VERSION 5.8 ;
BUSBITCHARS "[]" ;
DIVIDERCHAR "/" ;
UNITS
    DATABASE MICRONS 1000 ;
END UNITS

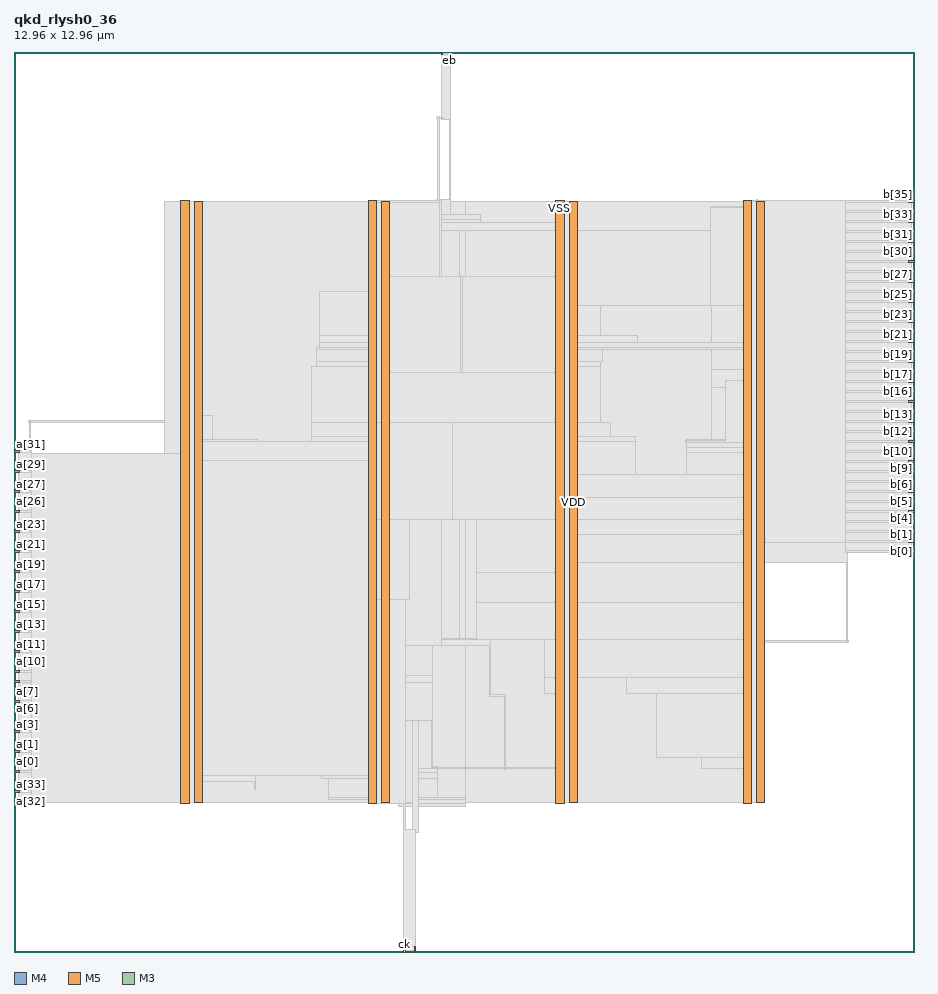
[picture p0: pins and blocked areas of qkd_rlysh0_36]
MACRO qkd_rlysh0_36
  FOREIGN qkd_rlysh0_36 0 0 ;
  CLASS BLOCK ;
  SIZE 12.96 BY 12.96 ;
  PIN a[0]
    DIRECTION INPUT ;
    USE SIGNAL ;
    PORT
      LAYER M4 ;
        RECT  0 2.736 0.084 2.76 ;
    END
  END a[0]
  PIN a[10]
    DIRECTION INPUT ;
    USE SIGNAL ;
    PORT
      LAYER M4 ;
        RECT  0 4.176 0.084 4.2 ;
    END
  END a[10]
  PIN a[11]
    DIRECTION INPUT ;
    USE SIGNAL ;
    PORT
      LAYER M4 ;
        RECT  0 4.32 0.084 4.344 ;
    END
  END a[11]
  PIN a[12]
    DIRECTION INPUT ;
    USE SIGNAL ;
    PORT
      LAYER M4 ;
        RECT  0 4.464 0.084 4.488 ;
    END
  END a[12]
  PIN a[13]
    DIRECTION INPUT ;
    USE SIGNAL ;
    PORT
      LAYER M4 ;
        RECT  0 4.608 0.084 4.632 ;
    END
  END a[13]
  PIN a[14]
    DIRECTION INPUT ;
    USE SIGNAL ;
    PORT
      LAYER M4 ;
        RECT  0 4.752 0.084 4.776 ;
    END
  END a[14]
  PIN a[15]
    DIRECTION INPUT ;
    USE SIGNAL ;
    PORT
      LAYER M4 ;
        RECT  0 4.896 0.084 4.92 ;
    END
  END a[15]
  PIN a[16]
    DIRECTION INPUT ;
    USE SIGNAL ;
    PORT
      LAYER M4 ;
        RECT  0 5.04 0.084 5.064 ;
    END
  END a[16]
  PIN a[17]
    DIRECTION INPUT ;
    USE SIGNAL ;
    PORT
      LAYER M4 ;
        RECT  0 5.184 0.084 5.208 ;
    END
  END a[17]
  PIN a[18]
    DIRECTION INPUT ;
    USE SIGNAL ;
    PORT
      LAYER M4 ;
        RECT  0 5.328 0.084 5.352 ;
    END
  END a[18]
  PIN a[19]
    DIRECTION INPUT ;
    USE SIGNAL ;
    PORT
      LAYER M4 ;
        RECT  0 5.472 0.084 5.496 ;
    END
  END a[19]
  PIN a[1]
    DIRECTION INPUT ;
    USE SIGNAL ;
    PORT
      LAYER M4 ;
        RECT  0 2.88 0.084 2.904 ;
    END
  END a[1]
  PIN a[20]
    DIRECTION INPUT ;
    USE SIGNAL ;
    PORT
      LAYER M4 ;
        RECT  0 5.616 0.084 5.64 ;
    END
  END a[20]
  PIN a[21]
    DIRECTION INPUT ;
    USE SIGNAL ;
    PORT
      LAYER M4 ;
        RECT  0 5.76 0.084 5.784 ;
    END
  END a[21]
  PIN a[22]
    DIRECTION INPUT ;
    USE SIGNAL ;
    PORT
      LAYER M4 ;
        RECT  0 5.904 0.084 5.928 ;
    END
  END a[22]
  PIN a[23]
    DIRECTION INPUT ;
    USE SIGNAL ;
    PORT
      LAYER M4 ;
        RECT  0 6.048 0.084 6.072 ;
    END
  END a[23]
  PIN a[24]
    DIRECTION INPUT ;
    USE SIGNAL ;
    PORT
      LAYER M4 ;
        RECT  0 6.192 0.084 6.216 ;
    END
  END a[24]
  PIN a[25]
    DIRECTION INPUT ;
    USE SIGNAL ;
    PORT
      LAYER M4 ;
        RECT  0 6.336 0.084 6.36 ;
    END
  END a[25]
  PIN a[26]
    DIRECTION INPUT ;
    USE SIGNAL ;
    PORT
      LAYER M4 ;
        RECT  0 6.48 0.084 6.504 ;
    END
  END a[26]
  PIN a[27]
    DIRECTION INPUT ;
    USE SIGNAL ;
    PORT
      LAYER M4 ;
        RECT  0 6.624 0.084 6.648 ;
    END
  END a[27]
  PIN a[28]
    DIRECTION INPUT ;
    USE SIGNAL ;
    PORT
      LAYER M4 ;
        RECT  0 6.768 0.084 6.792 ;
    END
  END a[28]
  PIN a[29]
    DIRECTION INPUT ;
    USE SIGNAL ;
    PORT
      LAYER M4 ;
        RECT  0 6.912 0.084 6.936 ;
    END
  END a[29]
  PIN a[2]
    DIRECTION INPUT ;
    USE SIGNAL ;
    PORT
      LAYER M4 ;
        RECT  0 3.024 0.084 3.048 ;
    END
  END a[2]
  PIN a[30]
    DIRECTION INPUT ;
    USE SIGNAL ;
    PORT
      LAYER M4 ;
        RECT  0 7.056 0.084 7.08 ;
    END
  END a[30]
  PIN a[31]
    DIRECTION INPUT ;
    USE SIGNAL ;
    PORT
      LAYER M4 ;
        RECT  0 7.2 0.084 7.224 ;
    END
  END a[31]
  PIN a[32]
    DIRECTION INPUT ;
    USE SIGNAL ;
    PORT
      LAYER M4 ;
        RECT  0 2.16 0.084 2.184 ;
    END
  END a[32]
  PIN a[33]
    DIRECTION INPUT ;
    USE SIGNAL ;
    PORT
      LAYER M4 ;
        RECT  0 2.304 0.084 2.328 ;
    END
  END a[33]
  PIN a[34]
    DIRECTION INPUT ;
    USE SIGNAL ;
    PORT
      LAYER M4 ;
        RECT  0 2.448 0.084 2.472 ;
    END
  END a[34]
  PIN a[35]
    DIRECTION INPUT ;
    USE SIGNAL ;
    PORT
      LAYER M4 ;
        RECT  0 2.592 0.084 2.616 ;
    END
  END a[35]
  PIN a[3]
    DIRECTION INPUT ;
    USE SIGNAL ;
    PORT
      LAYER M4 ;
        RECT  0 3.168 0.084 3.192 ;
    END
  END a[3]
  PIN a[4]
    DIRECTION INPUT ;
    USE SIGNAL ;
    PORT
      LAYER M4 ;
        RECT  0 3.312 0.084 3.336 ;
    END
  END a[4]
  PIN a[5]
    DIRECTION INPUT ;
    USE SIGNAL ;
    PORT
      LAYER M4 ;
        RECT  0 3.456 0.084 3.48 ;
    END
  END a[5]
  PIN a[6]
    DIRECTION INPUT ;
    USE SIGNAL ;
    PORT
      LAYER M4 ;
        RECT  0 3.6 0.084 3.624 ;
    END
  END a[6]
  PIN a[7]
    DIRECTION INPUT ;
    USE SIGNAL ;
    PORT
      LAYER M4 ;
        RECT  0 3.744 0.084 3.768 ;
    END
  END a[7]
  PIN a[8]
    DIRECTION INPUT ;
    USE SIGNAL ;
    PORT
      LAYER M4 ;
        RECT  0 3.888 0.084 3.912 ;
    END
  END a[8]
  PIN a[9]
    DIRECTION INPUT ;
    USE SIGNAL ;
    PORT
      LAYER M4 ;
        RECT  0 4.032 0.084 4.056 ;
    END
  END a[9]
  PIN b[0]
    DIRECTION OUTPUT ;
    USE SIGNAL ;
    PORT
      LAYER M4 ;
        RECT  12.876 5.76 12.96 5.784 ;
    END
  END b[0]
  PIN b[10]
    DIRECTION OUTPUT ;
    USE SIGNAL ;
    PORT
      LAYER M4 ;
        RECT  12.876 7.2 12.96 7.224 ;
    END
  END b[10]
  PIN b[11]
    DIRECTION OUTPUT ;
    USE SIGNAL ;
    PORT
      LAYER M4 ;
        RECT  12.876 7.344 12.96 7.368 ;
    END
  END b[11]
  PIN b[12]
    DIRECTION OUTPUT ;
    USE SIGNAL ;
    PORT
      LAYER M4 ;
        RECT  12.876 7.488 12.96 7.512 ;
    END
  END b[12]
  PIN b[13]
    DIRECTION OUTPUT ;
    USE SIGNAL ;
    PORT
      LAYER M4 ;
        RECT  12.876 7.632 12.96 7.656 ;
    END
  END b[13]
  PIN b[14]
    DIRECTION OUTPUT ;
    USE SIGNAL ;
    PORT
      LAYER M4 ;
        RECT  12.876 7.776 12.96 7.8 ;
    END
  END b[14]
  PIN b[15]
    DIRECTION OUTPUT ;
    USE SIGNAL ;
    PORT
      LAYER M4 ;
        RECT  12.876 7.92 12.96 7.944 ;
    END
  END b[15]
  PIN b[16]
    DIRECTION OUTPUT ;
    USE SIGNAL ;
    PORT
      LAYER M4 ;
        RECT  12.876 8.064 12.96 8.088 ;
    END
  END b[16]
  PIN b[17]
    DIRECTION OUTPUT ;
    USE SIGNAL ;
    PORT
      LAYER M4 ;
        RECT  12.876 8.208 12.96 8.232 ;
    END
  END b[17]
  PIN b[18]
    DIRECTION OUTPUT ;
    USE SIGNAL ;
    PORT
      LAYER M4 ;
        RECT  12.876 8.352 12.96 8.376 ;
    END
  END b[18]
  PIN b[19]
    DIRECTION OUTPUT ;
    USE SIGNAL ;
    PORT
      LAYER M4 ;
        RECT  12.876 8.496 12.96 8.52 ;
    END
  END b[19]
  PIN b[1]
    DIRECTION OUTPUT ;
    USE SIGNAL ;
    PORT
      LAYER M4 ;
        RECT  12.876 5.904 12.96 5.928 ;
    END
  END b[1]
  PIN b[20]
    DIRECTION OUTPUT ;
    USE SIGNAL ;
    PORT
      LAYER M4 ;
        RECT  12.876 8.64 12.96 8.664 ;
    END
  END b[20]
  PIN b[21]
    DIRECTION OUTPUT ;
    USE SIGNAL ;
    PORT
      LAYER M4 ;
        RECT  12.876 8.784 12.96 8.808 ;
    END
  END b[21]
  PIN b[22]
    DIRECTION OUTPUT ;
    USE SIGNAL ;
    PORT
      LAYER M4 ;
        RECT  12.876 8.928 12.96 8.952 ;
    END
  END b[22]
  PIN b[23]
    DIRECTION OUTPUT ;
    USE SIGNAL ;
    PORT
      LAYER M4 ;
        RECT  12.876 9.072 12.96 9.096 ;
    END
  END b[23]
  PIN b[24]
    DIRECTION OUTPUT ;
    USE SIGNAL ;
    PORT
      LAYER M4 ;
        RECT  12.876 9.216 12.96 9.24 ;
    END
  END b[24]
  PIN b[25]
    DIRECTION OUTPUT ;
    USE SIGNAL ;
    PORT
      LAYER M4 ;
        RECT  12.876 9.36 12.96 9.384 ;
    END
  END b[25]
  PIN b[26]
    DIRECTION OUTPUT ;
    USE SIGNAL ;
    PORT
      LAYER M4 ;
        RECT  12.876 9.504 12.96 9.528 ;
    END
  END b[26]
  PIN b[27]
    DIRECTION OUTPUT ;
    USE SIGNAL ;
    PORT
      LAYER M4 ;
        RECT  12.876 9.648 12.96 9.672 ;
    END
  END b[27]
  PIN b[28]
    DIRECTION OUTPUT ;
    USE SIGNAL ;
    PORT
      LAYER M4 ;
        RECT  12.876 9.792 12.96 9.816 ;
    END
  END b[28]
  PIN b[29]
    DIRECTION OUTPUT ;
    USE SIGNAL ;
    PORT
      LAYER M4 ;
        RECT  12.876 9.936 12.96 9.96 ;
    END
  END b[29]
  PIN b[2]
    DIRECTION OUTPUT ;
    USE SIGNAL ;
    PORT
      LAYER M4 ;
        RECT  12.876 6.048 12.96 6.072 ;
    END
  END b[2]
  PIN b[30]
    DIRECTION OUTPUT ;
    USE SIGNAL ;
    PORT
      LAYER M4 ;
        RECT  12.876 10.08 12.96 10.104 ;
    END
  END b[30]
  PIN b[31]
    DIRECTION OUTPUT ;
    USE SIGNAL ;
    PORT
      LAYER M4 ;
        RECT  12.876 10.224 12.96 10.248 ;
    END
  END b[31]
  PIN b[32]
    DIRECTION OUTPUT ;
    USE SIGNAL ;
    PORT
      LAYER M4 ;
        RECT  12.876 10.368 12.96 10.392 ;
    END
  END b[32]
  PIN b[33]
    DIRECTION OUTPUT ;
    USE SIGNAL ;
    PORT
      LAYER M4 ;
        RECT  12.876 10.512 12.96 10.536 ;
    END
  END b[33]
  PIN b[34]
    DIRECTION OUTPUT ;
    USE SIGNAL ;
    PORT
      LAYER M4 ;
        RECT  12.876 10.656 12.96 10.68 ;
    END
  END b[34]
  PIN b[35]
    DIRECTION OUTPUT ;
    USE SIGNAL ;
    PORT
      LAYER M4 ;
        RECT  12.876 10.8 12.96 10.824 ;
    END
  END b[35]
  PIN b[3]
    DIRECTION OUTPUT ;
    USE SIGNAL ;
    PORT
      LAYER M4 ;
        RECT  12.876 6.192 12.96 6.216 ;
    END
  END b[3]
  PIN b[4]
    DIRECTION OUTPUT ;
    USE SIGNAL ;
    PORT
      LAYER M4 ;
        RECT  12.876 6.336 12.96 6.36 ;
    END
  END b[4]
  PIN b[5]
    DIRECTION OUTPUT ;
    USE SIGNAL ;
    PORT
      LAYER M4 ;
        RECT  12.876 6.48 12.96 6.504 ;
    END
  END b[5]
  PIN b[6]
    DIRECTION OUTPUT ;
    USE SIGNAL ;
    PORT
      LAYER M4 ;
        RECT  12.876 6.624 12.96 6.648 ;
    END
  END b[6]
  PIN b[7]
    DIRECTION OUTPUT ;
    USE SIGNAL ;
    PORT
      LAYER M4 ;
        RECT  12.876 6.768 12.96 6.792 ;
    END
  END b[7]
  PIN b[8]
    DIRECTION OUTPUT ;
    USE SIGNAL ;
    PORT
      LAYER M4 ;
        RECT  12.876 6.912 12.96 6.936 ;
    END
  END b[8]
  PIN b[9]
    DIRECTION OUTPUT ;
    USE SIGNAL ;
    PORT
      LAYER M4 ;
        RECT  12.876 7.056 12.96 7.08 ;
    END
  END b[9]
  PIN ck
    DIRECTION INPUT ;
    USE SIGNAL ;
    PORT
      LAYER M5 ;
        RECT  5.616 0 5.64 0.084 ;
    END
  END ck
  PIN ck_o
    DIRECTION OUTPUT ;
    USE SIGNAL ;
    PORT
      LAYER M3 ;
        RECT  6.156 12.923 6.174 12.96 ;
    END
  END ck_o
  PIN eb
    DIRECTION OUTPUT ;
    USE SIGNAL ;
    PORT
      LAYER M3 ;
        RECT  6.264 12.923 6.282 12.96 ;
    END
  END eb
  PIN en
    DIRECTION INPUT ;
    USE SIGNAL ;
    PORT
      LAYER M5 ;
        RECT  5.76 0 5.784 0.084 ;
    END
  END en
  PIN VDD
    DIRECTION INOUT ;
    USE POWER ;
    PORT
      LAYER M5 ;
        RECT  10.692 2.151 10.812 10.809 ;
        RECT  7.992 2.151 8.112 10.809 ;
        RECT  5.292 2.151 5.412 10.809 ;
        RECT  2.592 2.151 2.712 10.809 ;
    END
  END VDD
  PIN VSS
    DIRECTION INOUT ;
    USE GROUND ;
    PORT
      LAYER M5 ;
        RECT  10.5 2.137 10.62 10.823 ;
        RECT  7.8 2.137 7.92 10.823 ;
        RECT  5.1 2.137 5.22 10.823 ;
        RECT  2.4 2.137 2.52 10.823 ;
    END
  END VSS
  # OT_OBS_CLOSED layer=M5 d_um=1.536 added=5
  OBS
    LAYER RVTN ;
     RECT  2.16 2.16 10.8 2.295 ;
     RECT  2.16 2.565 10.8 2.835 ;
     RECT  2.16 3.105 10.8 3.375 ;
     RECT  2.16 3.645 10.8 3.915 ;
     RECT  2.16 4.185 10.8 4.455 ;
     RECT  2.16 4.725 10.8 4.995 ;
     RECT  2.16 5.265 10.8 5.535 ;
     RECT  2.16 5.805 10.8 6.075 ;
     RECT  2.16 6.345 10.8 6.615 ;
     RECT  2.16 6.885 10.8 7.155 ;
     RECT  2.16 7.425 10.8 7.695 ;
     RECT  2.16 7.965 10.8 8.235 ;
     RECT  2.16 8.505 10.8 8.775 ;
     RECT  2.16 9.045 10.8 9.315 ;
     RECT  2.16 9.585 10.8 9.855 ;
     RECT  2.16 10.125 10.8 10.395 ;
     RECT  2.16 10.665 10.8 10.8 ;
    LAYER RVTP ;
     RECT  2.16 2.295 10.8 2.565 ;
     RECT  2.16 2.835 10.8 3.105 ;
     RECT  2.16 3.375 10.8 3.645 ;
     RECT  2.16 3.915 10.8 4.185 ;
     RECT  2.16 4.455 10.8 4.725 ;
     RECT  2.16 4.995 10.8 5.265 ;
     RECT  2.16 5.535 10.8 5.805 ;
     RECT  2.16 6.075 10.8 6.345 ;
     RECT  2.16 6.615 10.8 6.885 ;
     RECT  2.16 7.155 10.8 7.425 ;
     RECT  2.16 7.695 10.8 7.965 ;
     RECT  2.16 8.235 10.8 8.505 ;
     RECT  2.16 8.775 10.8 9.045 ;
     RECT  2.16 9.315 10.8 9.585 ;
     RECT  2.16 9.855 10.8 10.125 ;
     RECT  2.16 10.395 10.8 10.665 ;
    LAYER M1 ;
     RECT  2.16 2.151 10.8 10.809 ;
    LAYER M2 ;
     RECT  0.103 6.048 0.239 6.066 ;
     RECT  0.211 7.632 2.16 7.65 ;
     RECT  2.16 2.151 5.539 10.809 ;
     RECT  5.539 2.106 6.503 10.809 ;
     RECT  6.503 2.151 10.8 10.809 ;
     RECT  10.8 2.421 10.812 10.539 ;
     RECT  10.812 5.616 10.859 9.774 ;
     RECT  10.859 5.616 11.435 9.684 ;
     RECT  10.812 4.464 12.011 4.482 ;
     RECT  11.435 5.886 12.011 9.108 ;
     RECT  12.011 6.012 12.047 7.344 ;
     RECT  12.011 8.586 12.047 9.108 ;
     RECT  12.047 6.012 12.083 6.174 ;
     RECT  12.083 6.012 12.119 6.03 ;
     RECT  12.047 7.092 12.155 7.11 ;
     RECT  12.047 9.09 12.155 9.108 ;
    LAYER M3 ;
     RECT  5.796 1.723 5.814 2.101 ;
     RECT  5.544 2.101 6.498 2.143 ;
     RECT  2.415 2.143 2.505 2.155 ;
     RECT  5.115 2.143 6.498 2.191 ;
     RECT  4.536 2.191 6.498 2.219 ;
     RECT  2.304 2.155 2.505 2.413 ;
     RECT  7.815 2.143 7.905 2.413 ;
     RECT  10.515 2.143 10.605 2.413 ;
     RECT  2.304 2.413 2.697 2.443 ;
     RECT  2.268 2.443 2.697 2.461 ;
     RECT  3.456 2.335 3.474 2.461 ;
     RECT  4.536 2.219 6.102 2.497 ;
     RECT  2.268 2.461 3.474 2.573 ;
     RECT  2.304 2.573 3.474 2.587 ;
     RECT  4.428 2.497 6.102 2.587 ;
     RECT  10.515 2.413 10.797 2.641 ;
     RECT  2.304 2.587 6.102 2.669 ;
     RECT  9.9 2.641 10.797 2.803 ;
     RECT  2.304 2.669 6.03 3.065 ;
     RECT  2.304 3.065 3.402 3.643 ;
     RECT  7.056 2.635 7.074 3.685 ;
     RECT  6.84 3.685 7.074 3.713 ;
     RECT  7.815 2.413 8.097 3.721 ;
     RECT  9.252 2.803 10.797 3.721 ;
     RECT  2.268 3.643 3.402 3.773 ;
     RECT  2.304 3.773 3.402 3.883 ;
     RECT  4.14 3.065 6.03 3.883 ;
     RECT  7.632 3.721 8.097 3.955 ;
     RECT  8.82 3.721 10.797 3.955 ;
     RECT  2.304 3.883 6.03 3.983 ;
     RECT  3.456 3.983 6.03 4.411 ;
     RECT  6.84 3.713 6.858 4.411 ;
     RECT  3.456 4.411 6.858 4.495 ;
     RECT  7.632 3.955 10.797 4.495 ;
     RECT  0.144 4.315 0.162 4.891 ;
     RECT  0.144 4.891 0.198 5.021 ;
     RECT  2.304 3.983 2.697 5.035 ;
     RECT  3.456 4.495 10.797 5.035 ;
     RECT  2.304 5.035 10.797 5.611 ;
     RECT  11.988 4.459 12.006 5.611 ;
     RECT  0.144 5.021 0.162 5.899 ;
     RECT  2.304 5.611 12.006 6.007 ;
     RECT  0.144 5.899 0.342 6.043 ;
     RECT  0.108 6.043 0.342 6.077 ;
     RECT  0.108 6.077 0.126 6.08 ;
     RECT  2.304 6.007 12.114 6.221 ;
     RECT  2.304 6.221 11.142 6.539 ;
     RECT  2.415 6.539 11.142 6.881 ;
     RECT  11.988 6.221 12.114 7.087 ;
     RECT  0.144 7.051 0.162 7.181 ;
     RECT  9.684 6.881 11.142 7.195 ;
     RECT  11.988 7.087 12.15 7.195 ;
     RECT  9.684 7.195 12.15 7.259 ;
     RECT  2.415 6.881 8.946 7.349 ;
     RECT  9.684 7.259 10.854 7.373 ;
     RECT  2.415 7.349 3.51 7.385 ;
     RECT  9.72 7.373 10.854 7.385 ;
     RECT  4.284 7.349 8.946 7.421 ;
     RECT  4.284 7.421 8.586 7.619 ;
     RECT  0.216 7.195 0.234 7.655 ;
     RECT  2.415 7.385 2.862 7.727 ;
     RECT  10.044 7.385 10.854 8.131 ;
     RECT  10.044 8.131 10.89 8.381 ;
     RECT  4.284 7.619 8.442 8.429 ;
     RECT  4.356 8.429 8.442 8.509 ;
     RECT  4.356 8.509 8.478 8.671 ;
     RECT  10.044 8.381 10.797 8.671 ;
     RECT  4.356 8.671 10.797 8.699 ;
     RECT  4.392 8.699 10.797 8.771 ;
     RECT  4.392 8.771 8.982 8.879 ;
     RECT  11.988 7.259 12.15 9.211 ;
     RECT  11.988 9.211 12.798 9.341 ;
     RECT  4.392 8.879 8.442 9.509 ;
     RECT  10.044 8.771 10.797 9.589 ;
     RECT  10.044 9.589 10.89 9.661 ;
     RECT  11.988 9.341 12.078 9.661 ;
     RECT  10.044 9.661 12.078 9.677 ;
     RECT  5.115 9.509 8.442 9.779 ;
     RECT  10.044 9.677 11.43 10.109 ;
     RECT  5.115 9.779 8.097 10.499 ;
     RECT  10.044 10.109 10.89 10.541 ;
     RECT  2.415 7.727 2.697 10.547 ;
     RECT  5.115 10.499 6.714 10.547 ;
     RECT  7.815 10.499 8.097 10.547 ;
     RECT  10.044 10.541 10.797 10.547 ;
     RECT  5.976 10.547 6.714 10.625 ;
     RECT  10.044 10.547 10.71 10.733 ;
     RECT  2.415 10.547 2.505 10.817 ;
     RECT  5.115 10.547 5.205 10.817 ;
     RECT  7.815 10.547 7.905 10.817 ;
     RECT  10.515 10.733 10.71 10.817 ;
     RECT  6.084 10.625 6.282 10.829 ;
     RECT  10.692 10.817 10.71 10.829 ;
     RECT  6.264 10.829 6.282 11.995 ;
     RECT  6.156 11.995 6.282 12.923 ;
     RECT  6.174 12.923 6.264 12.941 ;
    LAYER M4 ;
     RECT  0.084 2.16 0.245 2.184 ;
     RECT  0.06 2.184 0.245 2.304 ;
     RECT  0.084 2.304 0.245 2.328 ;
     RECT  0.06 2.328 0.245 2.448 ;
     RECT  0.084 2.448 0.245 2.472 ;
     RECT  0.06 2.472 0.245 2.592 ;
     RECT  0.084 2.592 0.245 2.616 ;
     RECT  0.06 2.616 0.245 2.736 ;
     RECT  0.084 2.736 0.245 2.76 ;
     RECT  0.06 2.76 0.245 2.88 ;
     RECT  0.084 2.88 0.245 2.904 ;
     RECT  0.06 2.904 0.245 3.024 ;
     RECT  0.084 3.024 0.245 3.048 ;
     RECT  0.06 3.048 0.245 3.168 ;
     RECT  0.084 3.168 0.245 3.192 ;
     RECT  0.06 3.192 0.245 3.312 ;
     RECT  0.084 3.312 0.245 3.336 ;
     RECT  0.06 3.336 0.245 3.456 ;
     RECT  0.084 3.456 0.245 3.48 ;
     RECT  0.06 3.48 0.245 3.6 ;
     RECT  0.084 3.6 0.245 3.624 ;
     RECT  0.06 3.624 0.245 3.744 ;
     RECT  0.084 3.744 0.245 3.768 ;
     RECT  0.06 3.768 0.245 3.888 ;
     RECT  0.084 3.888 0.245 3.912 ;
     RECT  0.06 3.912 0.245 4.032 ;
     RECT  0.084 4.032 0.245 4.056 ;
     RECT  0.06 4.056 0.245 4.176 ;
     RECT  0.084 4.176 0.245 4.2 ;
     RECT  0.06 4.2 0.245 4.32 ;
     RECT  0.084 4.32 0.245 4.344 ;
     RECT  0.06 4.344 0.245 4.464 ;
     RECT  0.084 4.464 0.245 4.488 ;
     RECT  0.06 4.488 0.245 4.608 ;
     RECT  0.084 4.608 0.245 4.632 ;
     RECT  0.06 4.632 0.245 4.752 ;
     RECT  0.084 4.752 0.245 4.776 ;
     RECT  0.06 4.776 0.245 4.896 ;
     RECT  0.084 4.896 0.245 4.92 ;
     RECT  0.06 4.92 0.245 5.04 ;
     RECT  0.084 5.04 0.245 5.064 ;
     RECT  0.06 5.064 0.245 5.184 ;
     RECT  0.084 5.184 0.245 5.208 ;
     RECT  0.06 5.208 0.245 5.328 ;
     RECT  0.084 5.328 0.245 5.352 ;
     RECT  0.06 5.352 0.245 5.472 ;
     RECT  0.084 5.472 0.245 5.496 ;
     RECT  0.06 5.496 0.245 5.616 ;
     RECT  0.084 5.616 0.245 5.64 ;
     RECT  0.06 5.64 0.245 5.76 ;
     RECT  0.084 5.76 0.245 5.784 ;
     RECT  0.06 5.784 0.245 5.904 ;
     RECT  0.084 5.904 0.245 5.928 ;
     RECT  0.06 5.928 0.245 6.048 ;
     RECT  0.084 6.048 0.245 6.072 ;
     RECT  0.06 6.072 0.245 6.192 ;
     RECT  0.084 6.192 0.245 6.216 ;
     RECT  0.06 6.216 0.245 6.336 ;
     RECT  0.084 6.336 0.245 6.36 ;
     RECT  0.06 6.36 0.245 6.48 ;
     RECT  0.084 6.48 0.245 6.504 ;
     RECT  0.06 6.504 0.245 6.624 ;
     RECT  0.084 6.624 0.245 6.648 ;
     RECT  0.06 6.648 0.245 6.768 ;
     RECT  0.084 6.768 0.245 6.792 ;
     RECT  0.06 6.792 0.245 6.912 ;
     RECT  0.084 6.912 0.245 6.936 ;
     RECT  0.06 6.936 0.245 7.056 ;
     RECT  0.084 7.056 0.245 7.08 ;
     RECT  0.06 7.08 0.245 7.2 ;
     RECT  0.084 7.2 0.245 7.224 ;
     RECT  0.245 2.16 2.408 7.176 ;
     RECT  2.408 2.148 2.512 10.812 ;
     RECT  2.512 2.418 2.704 10.542 ;
     RECT  2.704 2.544 5.108 7.08 ;
     RECT  5.108 2.148 5.404 10.812 ;
     RECT  5.404 2.148 5.465 7.608 ;
     RECT  5.465 2.148 5.741 3.336 ;
     RECT  5.741 1.728 5.825 3.336 ;
     RECT  5.825 2.64 6.005 3.336 ;
     RECT  5.404 9.216 6.073 10.812 ;
     RECT  5.465 4.416 6.149 7.608 ;
     RECT  6.073 9.216 6.157 10.824 ;
     RECT  6.085 12 6.185 12.024 ;
     RECT  6.149 4.512 6.421 7.608 ;
     RECT  6.157 9.216 6.421 10.392 ;
     RECT  6.421 4.512 6.508 10.392 ;
     RECT  6.508 4.512 6.653 7.704 ;
     RECT  6.005 2.64 7.808 2.664 ;
     RECT  6.653 5.472 7.808 7.704 ;
     RECT  6.508 9.216 7.808 10.392 ;
     RECT  7.808 2.148 7.912 10.812 ;
     RECT  7.912 2.418 8.104 10.542 ;
     RECT  8.104 9.312 10.033 10.392 ;
     RECT  9.673 7.344 10.249 7.368 ;
     RECT  10.465 6.048 10.508 6.072 ;
     RECT  10.249 7.344 10.508 8.232 ;
     RECT  10.033 9.312 10.508 10.728 ;
     RECT  10.508 2.148 10.612 10.812 ;
     RECT  10.612 2.418 10.681 10.812 ;
     RECT  10.681 2.418 10.804 10.824 ;
     RECT  10.804 5.904 11.977 10.824 ;
     RECT  11.977 5.76 12.876 5.784 ;
     RECT  11.977 5.784 12.924 5.904 ;
     RECT  11.977 5.904 12.876 5.928 ;
     RECT  11.977 5.928 12.924 6.048 ;
     RECT  11.977 6.048 12.876 6.072 ;
     RECT  11.977 6.072 12.924 6.192 ;
     RECT  11.977 6.192 12.876 6.216 ;
     RECT  11.977 6.216 12.924 6.336 ;
     RECT  11.977 6.336 12.876 6.36 ;
     RECT  11.977 6.36 12.924 6.48 ;
     RECT  11.977 6.48 12.876 6.504 ;
     RECT  11.977 6.504 12.924 6.624 ;
     RECT  11.977 6.624 12.876 6.648 ;
     RECT  11.977 6.648 12.924 6.768 ;
     RECT  11.977 6.768 12.876 6.792 ;
     RECT  11.977 6.792 12.924 6.912 ;
     RECT  11.977 6.912 12.876 6.936 ;
     RECT  11.977 6.936 12.924 7.056 ;
     RECT  11.977 7.056 12.876 7.08 ;
     RECT  11.977 7.08 12.924 7.2 ;
     RECT  11.977 7.2 12.876 7.224 ;
     RECT  11.977 7.224 12.924 7.344 ;
     RECT  11.977 7.344 12.876 7.368 ;
     RECT  11.977 7.368 12.924 7.488 ;
     RECT  11.977 7.488 12.876 7.512 ;
     RECT  11.977 7.512 12.924 7.632 ;
     RECT  11.977 7.632 12.876 7.656 ;
     RECT  11.977 7.656 12.924 7.776 ;
     RECT  11.977 7.776 12.876 7.8 ;
     RECT  11.977 7.8 12.924 7.92 ;
     RECT  11.977 7.92 12.876 7.944 ;
     RECT  11.977 7.944 12.924 8.064 ;
     RECT  11.977 8.064 12.876 8.088 ;
     RECT  11.977 8.088 12.924 8.208 ;
     RECT  11.977 8.208 12.876 8.232 ;
     RECT  11.977 8.232 12.924 8.352 ;
     RECT  11.977 8.352 12.876 8.376 ;
     RECT  11.977 8.376 12.924 8.496 ;
     RECT  11.977 8.496 12.876 8.52 ;
     RECT  11.977 8.52 12.924 8.64 ;
     RECT  11.977 8.64 12.876 8.664 ;
     RECT  11.977 8.664 12.924 8.784 ;
     RECT  11.977 8.784 12.876 8.808 ;
     RECT  11.977 8.808 12.924 8.928 ;
     RECT  11.977 8.928 12.876 8.952 ;
     RECT  11.977 8.952 12.924 9.072 ;
     RECT  11.977 9.072 12.876 9.096 ;
     RECT  11.977 9.096 12.924 9.216 ;
     RECT  11.977 9.216 12.876 9.24 ;
     RECT  11.977 9.24 12.924 9.36 ;
     RECT  11.977 9.36 12.876 9.384 ;
     RECT  11.977 9.384 12.924 9.504 ;
     RECT  11.977 9.504 12.876 9.528 ;
     RECT  11.977 9.528 12.924 9.648 ;
     RECT  11.977 9.648 12.876 9.672 ;
     RECT  11.977 9.672 12.924 9.792 ;
     RECT  11.977 9.792 12.876 9.816 ;
     RECT  11.977 9.816 12.924 9.936 ;
     RECT  11.977 9.936 12.876 9.96 ;
     RECT  11.977 9.96 12.924 10.08 ;
     RECT  11.977 10.08 12.876 10.104 ;
     RECT  11.977 10.104 12.924 10.224 ;
     RECT  11.977 10.224 12.876 10.248 ;
     RECT  11.977 10.248 12.924 10.368 ;
     RECT  11.977 10.368 12.876 10.392 ;
     RECT  11.977 10.392 12.924 10.512 ;
     RECT  11.977 10.512 12.876 10.536 ;
     RECT  11.977 10.536 12.924 10.656 ;
     RECT  11.977 10.656 12.876 10.68 ;
     RECT  11.977 10.68 12.924 10.8 ;
     RECT  11.977 10.8 12.876 10.824 ;
    LAYER M5 ;
     RECT  5.64 0.016 5.76 0.084 ;
     RECT  5.616 0.084 5.784 1.763 ;
     RECT  5.616 1.763 5.64 2.137 ;
     RECT  2.4 2.137 2.52 2.151 ;
     RECT  7.8 2.137 7.92 2.151 ;
     RECT  10.5 2.137 10.62 2.151 ;
     RECT  5.1 2.137 5.64 5.077 ;
     RECT  5.1 5.077 5.688 6.229 ;
     RECT  5.1 6.229 6.312 7.619 ;
     RECT  6.432 8.341 6.456 9.731 ;
     RECT  5.1 7.619 5.412 10.789 ;
     RECT  2.4 2.151 2.712 10.809 ;
     RECT  7.8 2.151 8.112 10.809 ;
     RECT  10.5 2.151 10.812 10.809 ;
     RECT  2.4 10.809 2.52 10.823 ;
     RECT  5.1 10.789 6.12 10.823 ;
     RECT  7.8 10.809 7.92 10.823 ;
     RECT  10.5 10.809 10.62 10.823 ;
     RECT  6.096 10.823 6.12 12.035 ;
     RECT  6.312 6.229 7.8 7.619 ;
     RECT  5.412 7.619 7.8 8.341 ;
     RECT  5.412 8.341 6.432 9.731 ;
     RECT  6.456 8.341 7.8 9.731 ;
     RECT  5.412 9.731 6.12 10.789 ;
  END
END qkd_rlysh0_36
END LIBRARY
